VERSION 5.7 ;
  NOWIREEXTENSIONATPIN ON ;
  DIVIDERCHAR "/" ;
  BUSBITCHARS "[]" ;
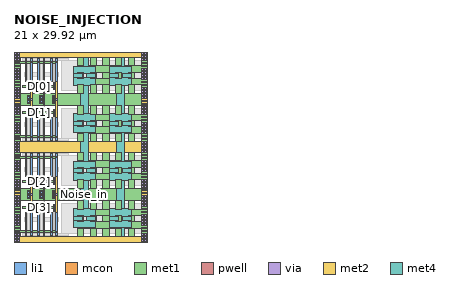
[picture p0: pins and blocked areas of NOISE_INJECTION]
MACRO NOISE_INJECTION
  CLASS BLOCK ;
  FOREIGN NOISE_INJECTION ;
  ORIGIN 0.000 0.000 ;
  SIZE 21.000 BY 29.920 ;
  PIN D[3]
    ANTENNAGATEAREA 0.378000 ;
    PORT
      LAYER li1 ;
        RECT 2.165 4.875 2.415 5.885 ;
        RECT 4.165 4.875 4.415 5.885 ;
        RECT 6.165 4.875 6.415 5.885 ;
      LAYER mcon ;
        RECT 2.205 5.295 2.375 5.465 ;
        RECT 4.205 5.295 4.375 5.465 ;
        RECT 6.205 5.295 6.375 5.465 ;
      LAYER met1 ;
        RECT 1.260 5.240 6.460 5.520 ;
    END
  END D[3]
  PIN VSS
    ANTENNADIFFAREA 3.813600 ;
    PORT
      LAYER pwell ;
        RECT 2.075 21.750 2.505 23.130 ;
        RECT 4.075 21.750 4.505 23.130 ;
        RECT 6.075 21.750 6.505 23.130 ;
        RECT 2.075 6.790 2.505 8.170 ;
        RECT 4.075 6.790 4.505 8.170 ;
        RECT 6.075 6.790 6.505 8.170 ;
      LAYER li1 ;
        RECT 1.735 25.295 1.985 28.825 ;
        RECT 2.595 25.295 2.845 28.825 ;
        RECT 3.735 25.295 3.985 28.825 ;
        RECT 4.595 25.295 4.845 28.825 ;
        RECT 5.735 25.295 5.985 28.825 ;
        RECT 6.595 25.295 6.845 28.825 ;
        RECT 2.165 21.935 2.415 22.945 ;
        RECT 4.165 21.935 4.415 22.945 ;
        RECT 6.165 21.935 6.415 22.945 ;
        RECT 1.735 16.055 1.985 19.585 ;
        RECT 2.595 16.055 2.845 19.585 ;
        RECT 3.735 16.055 3.985 19.585 ;
        RECT 4.595 16.055 4.845 19.585 ;
        RECT 5.735 16.055 5.985 19.585 ;
        RECT 6.595 16.055 6.845 19.585 ;
        RECT 1.735 10.335 1.985 13.865 ;
        RECT 2.595 10.335 2.845 13.865 ;
        RECT 3.735 10.335 3.985 13.865 ;
        RECT 4.595 10.335 4.845 13.865 ;
        RECT 5.735 10.335 5.985 13.865 ;
        RECT 6.595 10.335 6.845 13.865 ;
        RECT 2.165 6.975 2.415 7.985 ;
        RECT 4.165 6.975 4.415 7.985 ;
        RECT 6.165 6.975 6.415 7.985 ;
        RECT 1.735 1.095 1.985 4.625 ;
        RECT 2.595 1.095 2.845 4.625 ;
        RECT 3.735 1.095 3.985 4.625 ;
        RECT 4.595 1.095 4.845 4.625 ;
        RECT 5.735 1.095 5.985 4.625 ;
        RECT 6.595 1.095 6.845 4.625 ;
      LAYER mcon ;
        RECT 1.775 28.235 1.945 28.405 ;
        RECT 2.635 28.235 2.805 28.405 ;
        RECT 3.775 28.235 3.945 28.405 ;
        RECT 4.635 28.235 4.805 28.405 ;
        RECT 5.775 28.235 5.945 28.405 ;
        RECT 6.635 28.235 6.805 28.405 ;
        RECT 2.205 22.355 2.375 22.525 ;
        RECT 4.205 22.355 4.375 22.525 ;
        RECT 6.205 22.355 6.375 22.525 ;
        RECT 1.775 16.475 1.945 16.645 ;
        RECT 2.635 16.475 2.805 16.645 ;
        RECT 3.775 16.475 3.945 16.645 ;
        RECT 4.635 16.475 4.805 16.645 ;
        RECT 5.775 16.475 5.945 16.645 ;
        RECT 6.635 16.475 6.805 16.645 ;
        RECT 1.775 13.275 1.945 13.445 ;
        RECT 2.635 13.275 2.805 13.445 ;
        RECT 3.775 13.275 3.945 13.445 ;
        RECT 4.635 13.275 4.805 13.445 ;
        RECT 5.775 13.275 5.945 13.445 ;
        RECT 6.635 13.275 6.805 13.445 ;
        RECT 2.205 7.395 2.375 7.565 ;
        RECT 4.205 7.395 4.375 7.565 ;
        RECT 6.205 7.395 6.375 7.565 ;
        RECT 1.775 1.515 1.945 1.685 ;
        RECT 2.635 1.515 2.805 1.685 ;
        RECT 3.775 1.515 3.945 1.685 ;
        RECT 4.635 1.515 4.805 1.685 ;
        RECT 5.775 1.515 5.945 1.685 ;
        RECT 6.635 1.515 6.805 1.685 ;
      LAYER met1 ;
        RECT 0.000 29.060 21.000 29.920 ;
        RECT 0.000 28.460 1.000 29.060 ;
        RECT 0.000 28.180 6.890 28.460 ;
        RECT 0.000 23.460 1.000 28.180 ;
        RECT 10.000 27.770 11.000 29.060 ;
        RECT 12.000 27.770 13.000 29.060 ;
        RECT 14.000 27.770 15.000 29.060 ;
        RECT 16.000 27.770 17.000 29.060 ;
        RECT 18.000 27.770 19.000 29.060 ;
        RECT 20.000 27.770 21.000 29.060 ;
        RECT 10.000 26.770 21.000 27.770 ;
        RECT 10.000 25.760 11.000 26.770 ;
        RECT 12.000 25.760 13.000 26.770 ;
        RECT 14.000 25.760 15.000 26.770 ;
        RECT 16.000 25.760 17.000 26.770 ;
        RECT 18.000 25.760 19.000 26.770 ;
        RECT 20.000 25.760 21.000 26.770 ;
        RECT 10.000 24.760 21.000 25.760 ;
        RECT 10.000 23.460 11.000 24.760 ;
        RECT 12.000 23.460 13.000 24.760 ;
        RECT 14.000 23.460 15.000 24.760 ;
        RECT 16.000 23.460 17.000 24.760 ;
        RECT 18.000 23.460 19.000 24.760 ;
        RECT 20.000 23.460 21.000 24.760 ;
        RECT 0.000 21.420 21.000 23.460 ;
        RECT 0.000 16.700 1.000 21.420 ;
        RECT 10.000 20.120 11.000 21.420 ;
        RECT 12.000 20.120 13.000 21.420 ;
        RECT 14.000 20.120 15.000 21.420 ;
        RECT 16.000 20.120 17.000 21.420 ;
        RECT 18.000 20.120 19.000 21.420 ;
        RECT 20.000 20.120 21.000 21.420 ;
        RECT 10.000 19.120 21.000 20.120 ;
        RECT 10.000 18.120 11.000 19.120 ;
        RECT 12.000 18.120 13.000 19.120 ;
        RECT 14.000 18.120 15.000 19.120 ;
        RECT 16.000 18.120 17.000 19.120 ;
        RECT 18.000 18.120 19.000 19.120 ;
        RECT 20.000 18.120 21.000 19.120 ;
        RECT 10.000 17.120 21.000 18.120 ;
        RECT 0.000 16.420 6.890 16.700 ;
        RECT 0.000 15.820 1.000 16.420 ;
        RECT 10.000 15.820 11.000 17.120 ;
        RECT 12.000 15.820 13.000 17.120 ;
        RECT 14.000 15.820 15.000 17.120 ;
        RECT 16.000 15.820 17.000 17.120 ;
        RECT 18.000 15.820 19.000 17.120 ;
        RECT 20.000 15.820 21.000 17.120 ;
        RECT 0.000 14.100 21.000 15.820 ;
        RECT 0.000 13.500 1.000 14.100 ;
        RECT 0.000 13.220 6.890 13.500 ;
        RECT 0.000 8.500 1.000 13.220 ;
        RECT 10.000 12.810 11.000 14.100 ;
        RECT 12.000 12.810 13.000 14.100 ;
        RECT 14.000 12.810 15.000 14.100 ;
        RECT 16.000 12.810 17.000 14.100 ;
        RECT 18.000 12.810 19.000 14.100 ;
        RECT 20.000 12.810 21.000 14.100 ;
        RECT 10.000 11.810 21.000 12.810 ;
        RECT 10.000 10.800 11.000 11.810 ;
        RECT 12.000 10.800 13.000 11.810 ;
        RECT 14.000 10.800 15.000 11.810 ;
        RECT 16.000 10.800 17.000 11.810 ;
        RECT 18.000 10.800 19.000 11.810 ;
        RECT 20.000 10.800 21.000 11.810 ;
        RECT 10.000 9.800 21.000 10.800 ;
        RECT 10.000 8.500 11.000 9.800 ;
        RECT 12.000 8.500 13.000 9.800 ;
        RECT 14.000 8.500 15.000 9.800 ;
        RECT 16.000 8.500 17.000 9.800 ;
        RECT 18.000 8.500 19.000 9.800 ;
        RECT 20.000 8.500 21.000 9.800 ;
        RECT 0.000 6.460 21.000 8.500 ;
        RECT 0.000 1.740 1.000 6.460 ;
        RECT 10.000 5.160 11.000 6.460 ;
        RECT 12.000 5.160 13.000 6.460 ;
        RECT 14.000 5.160 15.000 6.460 ;
        RECT 16.000 5.160 17.000 6.460 ;
        RECT 18.000 5.160 19.000 6.460 ;
        RECT 20.000 5.160 21.000 6.460 ;
        RECT 10.000 4.160 21.000 5.160 ;
        RECT 10.000 3.160 11.000 4.160 ;
        RECT 12.000 3.160 13.000 4.160 ;
        RECT 14.000 3.160 15.000 4.160 ;
        RECT 16.000 3.160 17.000 4.160 ;
        RECT 18.000 3.160 19.000 4.160 ;
        RECT 20.000 3.160 21.000 4.160 ;
        RECT 10.000 2.160 21.000 3.160 ;
        RECT 0.000 1.460 6.890 1.740 ;
        RECT 0.000 0.860 1.000 1.460 ;
        RECT 10.000 0.860 11.000 2.160 ;
        RECT 12.000 0.860 13.000 2.160 ;
        RECT 14.000 0.860 15.000 2.160 ;
        RECT 16.000 0.860 17.000 2.160 ;
        RECT 18.000 0.860 19.000 2.160 ;
        RECT 20.000 0.860 21.000 2.160 ;
        RECT 0.000 0.000 21.000 0.860 ;
      LAYER via ;
        RECT 0.120 29.580 0.380 29.840 ;
        RECT 0.620 29.580 0.880 29.840 ;
        RECT 20.120 29.580 20.380 29.840 ;
        RECT 20.620 29.580 20.880 29.840 ;
        RECT 0.120 29.080 0.380 29.340 ;
        RECT 0.620 29.080 0.880 29.340 ;
        RECT 20.120 29.080 20.380 29.340 ;
        RECT 20.620 29.080 20.880 29.340 ;
        RECT 0.120 28.580 0.380 28.840 ;
        RECT 0.620 28.580 0.880 28.840 ;
        RECT 0.120 28.080 0.380 28.340 ;
        RECT 0.620 28.080 0.880 28.340 ;
        RECT 2.590 28.190 2.850 28.450 ;
        RECT 4.590 28.190 4.850 28.450 ;
        RECT 6.590 28.190 6.850 28.450 ;
        RECT 0.120 27.580 0.380 27.840 ;
        RECT 0.620 27.580 0.880 27.840 ;
        RECT 0.120 27.080 0.380 27.340 ;
        RECT 0.620 27.080 0.880 27.340 ;
        RECT 0.120 26.580 0.380 26.840 ;
        RECT 0.620 26.580 0.880 26.840 ;
        RECT 0.120 26.080 0.380 26.340 ;
        RECT 0.620 26.080 0.880 26.340 ;
        RECT 0.120 25.580 0.380 25.840 ;
        RECT 0.620 25.580 0.880 25.840 ;
        RECT 0.120 25.080 0.380 25.340 ;
        RECT 0.620 25.080 0.880 25.340 ;
        RECT 0.120 24.580 0.380 24.840 ;
        RECT 0.620 24.580 0.880 24.840 ;
        RECT 0.120 24.080 0.380 24.340 ;
        RECT 0.620 24.080 0.880 24.340 ;
        RECT 0.120 23.580 0.380 23.840 ;
        RECT 0.620 23.580 0.880 23.840 ;
        RECT 20.120 28.580 20.380 28.840 ;
        RECT 20.620 28.580 20.880 28.840 ;
        RECT 20.120 28.080 20.380 28.340 ;
        RECT 20.620 28.080 20.880 28.340 ;
        RECT 20.120 27.580 20.380 27.840 ;
        RECT 20.620 27.580 20.880 27.840 ;
        RECT 20.120 27.080 20.380 27.340 ;
        RECT 20.620 27.080 20.880 27.340 ;
        RECT 20.120 26.580 20.380 26.840 ;
        RECT 20.620 26.580 20.880 26.840 ;
        RECT 20.120 26.080 20.380 26.340 ;
        RECT 20.620 26.080 20.880 26.340 ;
        RECT 20.120 25.580 20.380 25.840 ;
        RECT 20.620 25.580 20.880 25.840 ;
        RECT 20.120 25.080 20.380 25.340 ;
        RECT 20.620 25.080 20.880 25.340 ;
        RECT 20.120 24.580 20.380 24.840 ;
        RECT 20.620 24.580 20.880 24.840 ;
        RECT 20.120 24.080 20.380 24.340 ;
        RECT 20.620 24.080 20.880 24.340 ;
        RECT 20.120 23.580 20.380 23.840 ;
        RECT 20.620 23.580 20.880 23.840 ;
        RECT 0.120 23.080 0.380 23.340 ;
        RECT 0.620 23.080 0.880 23.340 ;
        RECT 20.120 23.080 20.380 23.340 ;
        RECT 20.620 23.080 20.880 23.340 ;
        RECT 0.120 22.580 0.380 22.840 ;
        RECT 0.620 22.580 0.880 22.840 ;
        RECT 20.120 22.580 20.380 22.840 ;
        RECT 20.620 22.580 20.880 22.840 ;
        RECT 0.120 22.080 0.380 22.340 ;
        RECT 0.620 22.080 0.880 22.340 ;
        RECT 2.590 22.310 2.850 22.570 ;
        RECT 4.590 22.310 4.850 22.570 ;
        RECT 6.590 22.310 6.850 22.570 ;
        RECT 20.120 22.080 20.380 22.340 ;
        RECT 20.620 22.080 20.880 22.340 ;
        RECT 0.120 21.580 0.380 21.840 ;
        RECT 0.620 21.580 0.880 21.840 ;
        RECT 20.120 21.580 20.380 21.840 ;
        RECT 20.620 21.580 20.880 21.840 ;
        RECT 0.120 21.080 0.380 21.340 ;
        RECT 0.620 21.080 0.880 21.340 ;
        RECT 0.120 20.580 0.380 20.840 ;
        RECT 0.620 20.580 0.880 20.840 ;
        RECT 0.120 20.080 0.380 20.340 ;
        RECT 0.620 20.080 0.880 20.340 ;
        RECT 0.120 19.580 0.380 19.840 ;
        RECT 0.620 19.580 0.880 19.840 ;
        RECT 0.120 19.080 0.380 19.340 ;
        RECT 0.620 19.080 0.880 19.340 ;
        RECT 0.120 18.580 0.380 18.840 ;
        RECT 0.620 18.580 0.880 18.840 ;
        RECT 0.120 18.080 0.380 18.340 ;
        RECT 0.620 18.080 0.880 18.340 ;
        RECT 0.120 17.580 0.380 17.840 ;
        RECT 0.620 17.580 0.880 17.840 ;
        RECT 0.120 17.080 0.380 17.340 ;
        RECT 0.620 17.080 0.880 17.340 ;
        RECT 0.120 16.580 0.380 16.840 ;
        RECT 0.620 16.580 0.880 16.840 ;
        RECT 20.120 21.080 20.380 21.340 ;
        RECT 20.620 21.080 20.880 21.340 ;
        RECT 20.120 20.580 20.380 20.840 ;
        RECT 20.620 20.580 20.880 20.840 ;
        RECT 20.120 20.080 20.380 20.340 ;
        RECT 20.620 20.080 20.880 20.340 ;
        RECT 20.120 19.580 20.380 19.840 ;
        RECT 20.620 19.580 20.880 19.840 ;
        RECT 20.120 19.080 20.380 19.340 ;
        RECT 20.620 19.080 20.880 19.340 ;
        RECT 20.120 18.580 20.380 18.840 ;
        RECT 20.620 18.580 20.880 18.840 ;
        RECT 20.120 18.080 20.380 18.340 ;
        RECT 20.620 18.080 20.880 18.340 ;
        RECT 20.120 17.580 20.380 17.840 ;
        RECT 20.620 17.580 20.880 17.840 ;
        RECT 2.590 16.430 2.850 16.690 ;
        RECT 4.590 16.430 4.850 16.690 ;
        RECT 6.590 16.430 6.850 16.690 ;
        RECT 0.120 16.080 0.380 16.340 ;
        RECT 0.620 16.080 0.880 16.340 ;
        RECT 0.120 15.580 0.380 15.840 ;
        RECT 0.620 15.580 0.880 15.840 ;
        RECT 20.120 17.080 20.380 17.340 ;
        RECT 20.620 17.080 20.880 17.340 ;
        RECT 20.120 16.580 20.380 16.840 ;
        RECT 20.620 16.580 20.880 16.840 ;
        RECT 20.120 16.080 20.380 16.340 ;
        RECT 20.620 16.080 20.880 16.340 ;
        RECT 20.120 15.580 20.380 15.840 ;
        RECT 20.620 15.580 20.880 15.840 ;
        RECT 0.120 15.080 0.380 15.340 ;
        RECT 0.620 15.080 0.880 15.340 ;
        RECT 20.120 15.080 20.380 15.340 ;
        RECT 20.620 15.080 20.880 15.340 ;
        RECT 0.120 14.580 0.380 14.840 ;
        RECT 0.620 14.580 0.880 14.840 ;
        RECT 20.120 14.580 20.380 14.840 ;
        RECT 20.620 14.580 20.880 14.840 ;
        RECT 0.120 14.080 0.380 14.340 ;
        RECT 0.620 14.080 0.880 14.340 ;
        RECT 0.120 13.580 0.380 13.840 ;
        RECT 0.620 13.580 0.880 13.840 ;
        RECT 0.120 13.080 0.380 13.340 ;
        RECT 0.620 13.080 0.880 13.340 ;
        RECT 2.590 13.230 2.850 13.490 ;
        RECT 4.590 13.230 4.850 13.490 ;
        RECT 6.590 13.230 6.850 13.490 ;
        RECT 0.120 12.580 0.380 12.840 ;
        RECT 0.620 12.580 0.880 12.840 ;
        RECT 0.120 12.080 0.380 12.340 ;
        RECT 0.620 12.080 0.880 12.340 ;
        RECT 0.120 11.580 0.380 11.840 ;
        RECT 0.620 11.580 0.880 11.840 ;
        RECT 0.120 11.080 0.380 11.340 ;
        RECT 0.620 11.080 0.880 11.340 ;
        RECT 0.120 10.580 0.380 10.840 ;
        RECT 0.620 10.580 0.880 10.840 ;
        RECT 0.120 10.080 0.380 10.340 ;
        RECT 0.620 10.080 0.880 10.340 ;
        RECT 0.120 9.580 0.380 9.840 ;
        RECT 0.620 9.580 0.880 9.840 ;
        RECT 0.120 9.080 0.380 9.340 ;
        RECT 0.620 9.080 0.880 9.340 ;
        RECT 0.120 8.580 0.380 8.840 ;
        RECT 0.620 8.580 0.880 8.840 ;
        RECT 20.120 14.080 20.380 14.340 ;
        RECT 20.620 14.080 20.880 14.340 ;
        RECT 20.120 13.580 20.380 13.840 ;
        RECT 20.620 13.580 20.880 13.840 ;
        RECT 20.120 13.080 20.380 13.340 ;
        RECT 20.620 13.080 20.880 13.340 ;
        RECT 20.120 12.580 20.380 12.840 ;
        RECT 20.620 12.580 20.880 12.840 ;
        RECT 20.120 12.080 20.380 12.340 ;
        RECT 20.620 12.080 20.880 12.340 ;
        RECT 20.120 11.580 20.380 11.840 ;
        RECT 20.620 11.580 20.880 11.840 ;
        RECT 20.120 11.080 20.380 11.340 ;
        RECT 20.620 11.080 20.880 11.340 ;
        RECT 20.120 10.580 20.380 10.840 ;
        RECT 20.620 10.580 20.880 10.840 ;
        RECT 20.120 10.080 20.380 10.340 ;
        RECT 20.620 10.080 20.880 10.340 ;
        RECT 20.120 9.580 20.380 9.840 ;
        RECT 20.620 9.580 20.880 9.840 ;
        RECT 20.120 9.080 20.380 9.340 ;
        RECT 20.620 9.080 20.880 9.340 ;
        RECT 20.120 8.580 20.380 8.840 ;
        RECT 20.620 8.580 20.880 8.840 ;
        RECT 0.120 8.080 0.380 8.340 ;
        RECT 0.620 8.080 0.880 8.340 ;
        RECT 20.120 8.080 20.380 8.340 ;
        RECT 20.620 8.080 20.880 8.340 ;
        RECT 0.120 7.580 0.380 7.840 ;
        RECT 0.620 7.580 0.880 7.840 ;
        RECT 2.590 7.350 2.850 7.610 ;
        RECT 4.590 7.350 4.850 7.610 ;
        RECT 6.590 7.350 6.850 7.610 ;
        RECT 20.120 7.580 20.380 7.840 ;
        RECT 20.620 7.580 20.880 7.840 ;
        RECT 0.120 7.080 0.380 7.340 ;
        RECT 0.620 7.080 0.880 7.340 ;
        RECT 20.120 7.080 20.380 7.340 ;
        RECT 20.620 7.080 20.880 7.340 ;
        RECT 0.120 6.580 0.380 6.840 ;
        RECT 0.620 6.580 0.880 6.840 ;
        RECT 20.120 6.580 20.380 6.840 ;
        RECT 20.620 6.580 20.880 6.840 ;
        RECT 0.120 6.080 0.380 6.340 ;
        RECT 0.620 6.080 0.880 6.340 ;
        RECT 0.120 5.580 0.380 5.840 ;
        RECT 0.620 5.580 0.880 5.840 ;
        RECT 0.120 5.080 0.380 5.340 ;
        RECT 0.620 5.080 0.880 5.340 ;
        RECT 0.120 4.580 0.380 4.840 ;
        RECT 0.620 4.580 0.880 4.840 ;
        RECT 0.120 4.080 0.380 4.340 ;
        RECT 0.620 4.080 0.880 4.340 ;
        RECT 0.120 3.580 0.380 3.840 ;
        RECT 0.620 3.580 0.880 3.840 ;
        RECT 0.120 3.080 0.380 3.340 ;
        RECT 0.620 3.080 0.880 3.340 ;
        RECT 0.120 2.580 0.380 2.840 ;
        RECT 0.620 2.580 0.880 2.840 ;
        RECT 0.120 2.080 0.380 2.340 ;
        RECT 0.620 2.080 0.880 2.340 ;
        RECT 0.120 1.580 0.380 1.840 ;
        RECT 0.620 1.580 0.880 1.840 ;
        RECT 20.120 6.080 20.380 6.340 ;
        RECT 20.620 6.080 20.880 6.340 ;
        RECT 20.120 5.580 20.380 5.840 ;
        RECT 20.620 5.580 20.880 5.840 ;
        RECT 20.120 5.080 20.380 5.340 ;
        RECT 20.620 5.080 20.880 5.340 ;
        RECT 20.120 4.580 20.380 4.840 ;
        RECT 20.620 4.580 20.880 4.840 ;
        RECT 20.120 4.080 20.380 4.340 ;
        RECT 20.620 4.080 20.880 4.340 ;
        RECT 20.120 3.580 20.380 3.840 ;
        RECT 20.620 3.580 20.880 3.840 ;
        RECT 20.120 3.080 20.380 3.340 ;
        RECT 20.620 3.080 20.880 3.340 ;
        RECT 20.120 2.580 20.380 2.840 ;
        RECT 20.620 2.580 20.880 2.840 ;
        RECT 2.590 1.470 2.850 1.730 ;
        RECT 4.590 1.470 4.850 1.730 ;
        RECT 6.590 1.470 6.850 1.730 ;
        RECT 0.120 1.080 0.380 1.340 ;
        RECT 0.620 1.080 0.880 1.340 ;
        RECT 20.120 2.080 20.380 2.340 ;
        RECT 20.620 2.080 20.880 2.340 ;
        RECT 20.120 1.580 20.380 1.840 ;
        RECT 20.620 1.580 20.880 1.840 ;
        RECT 20.120 1.080 20.380 1.340 ;
        RECT 20.620 1.080 20.880 1.340 ;
        RECT 0.120 0.580 0.380 0.840 ;
        RECT 0.620 0.580 0.880 0.840 ;
        RECT 20.120 0.580 20.380 0.840 ;
        RECT 20.620 0.580 20.880 0.840 ;
        RECT 0.120 0.080 0.380 0.340 ;
        RECT 0.620 0.080 0.880 0.340 ;
        RECT 20.120 0.080 20.380 0.340 ;
        RECT 20.620 0.080 20.880 0.340 ;
      LAYER met2 ;
        RECT 0.000 29.060 21.000 29.920 ;
        RECT 0.000 15.820 1.000 29.060 ;
        RECT 2.580 16.400 2.860 28.480 ;
        RECT 4.580 16.400 4.860 28.480 ;
        RECT 6.580 16.400 6.860 28.480 ;
        RECT 20.000 15.820 21.000 29.060 ;
        RECT 0.000 14.100 21.000 15.820 ;
        RECT 0.000 0.860 1.000 14.100 ;
        RECT 2.580 1.440 2.860 13.520 ;
        RECT 4.580 1.440 4.860 13.520 ;
        RECT 6.580 1.440 6.860 13.520 ;
        RECT 20.000 0.860 21.000 14.100 ;
        RECT 0.000 0.000 21.000 0.860 ;
    END
  END VSS
  PIN D[2]
    ANTENNAGATEAREA 0.378000 ;
    PORT
      LAYER li1 ;
        RECT 2.165 9.075 2.415 10.085 ;
        RECT 4.165 9.075 4.415 10.085 ;
        RECT 6.165 9.075 6.415 10.085 ;
      LAYER mcon ;
        RECT 2.205 9.495 2.375 9.665 ;
        RECT 4.205 9.495 4.375 9.665 ;
        RECT 6.205 9.495 6.375 9.665 ;
      LAYER met1 ;
        RECT 1.260 9.440 6.460 9.720 ;
    END
  END D[2]
  PIN D[1]
    ANTENNAGATEAREA 0.378000 ;
    PORT
      LAYER li1 ;
        RECT 2.165 19.835 2.415 20.845 ;
        RECT 4.165 19.835 4.415 20.845 ;
        RECT 6.165 19.835 6.415 20.845 ;
      LAYER mcon ;
        RECT 2.205 20.255 2.375 20.425 ;
        RECT 4.205 20.255 4.375 20.425 ;
        RECT 6.205 20.255 6.375 20.425 ;
      LAYER met1 ;
        RECT 1.260 20.200 6.460 20.480 ;
    END
  END D[1]
  PIN D[0]
    ANTENNAGATEAREA 0.378000 ;
    PORT
      LAYER li1 ;
        RECT 2.165 24.035 2.415 25.045 ;
        RECT 4.165 24.035 4.415 25.045 ;
        RECT 6.165 24.035 6.415 25.045 ;
      LAYER mcon ;
        RECT 2.205 24.455 2.375 24.625 ;
        RECT 4.205 24.455 4.375 24.625 ;
        RECT 6.205 24.455 6.375 24.625 ;
      LAYER met1 ;
        RECT 1.260 24.400 6.460 24.680 ;
    END
  END D[0]
  PIN Noise_in
    PORT
      LAYER met4 ;
        RECT 10.500 27.710 11.700 29.060 ;
        RECT 9.300 26.510 12.900 27.710 ;
        RECT 9.300 25.910 10.800 26.510 ;
        RECT 11.400 25.910 12.900 26.510 ;
        RECT 9.300 24.710 12.900 25.910 ;
        RECT 10.500 20.170 11.700 24.710 ;
        RECT 9.300 18.970 12.900 20.170 ;
        RECT 9.300 18.370 10.800 18.970 ;
        RECT 11.400 18.370 12.900 18.970 ;
        RECT 9.300 17.170 12.900 18.370 ;
        RECT 10.500 12.750 11.700 17.170 ;
        RECT 9.300 11.550 12.900 12.750 ;
        RECT 9.300 10.950 10.800 11.550 ;
        RECT 11.400 10.950 12.900 11.550 ;
        RECT 9.300 9.750 12.900 10.950 ;
        RECT 10.500 5.210 11.700 9.750 ;
        RECT 9.300 4.010 12.900 5.210 ;
        RECT 9.300 3.410 10.800 4.010 ;
        RECT 11.400 3.410 12.900 4.010 ;
        RECT 9.300 2.210 12.900 3.410 ;
    END
  END Noise_in
  PIN bias_out
    PORT
      LAYER met4 ;
        RECT 16.170 27.710 17.370 29.060 ;
        RECT 14.970 26.510 18.570 27.710 ;
        RECT 14.970 25.910 16.470 26.510 ;
        RECT 17.070 25.910 18.570 26.510 ;
        RECT 14.970 24.710 18.570 25.910 ;
        RECT 16.170 20.170 17.370 24.710 ;
        RECT 14.970 18.970 18.570 20.170 ;
        RECT 14.970 18.370 16.470 18.970 ;
        RECT 17.070 18.370 18.570 18.970 ;
        RECT 14.970 17.170 18.570 18.370 ;
        RECT 16.170 12.750 17.370 17.170 ;
        RECT 14.970 11.550 18.570 12.750 ;
        RECT 14.970 10.950 16.470 11.550 ;
        RECT 17.070 10.950 18.570 11.550 ;
        RECT 14.970 9.750 18.570 10.950 ;
        RECT 16.170 5.210 17.370 9.750 ;
        RECT 14.970 4.010 18.570 5.210 ;
        RECT 14.970 3.410 16.470 4.010 ;
        RECT 17.070 3.410 18.570 4.010 ;
        RECT 14.970 2.210 18.570 3.410 ;
        RECT 16.170 0.860 17.370 2.210 ;
    END
  END bias_out
  OBS
      LAYER pwell ;
        RECT 1.605 25.985 6.975 26.665 ;
        RECT 1.605 18.215 6.975 18.895 ;
        RECT 1.605 11.025 6.975 11.705 ;
        RECT 1.605 3.255 6.975 3.935 ;
      LAYER li1 ;
        RECT 2.165 25.295 2.415 28.825 ;
        RECT 4.165 25.295 4.415 28.825 ;
        RECT 6.165 25.295 6.415 28.825 ;
        RECT 2.165 16.055 2.415 19.585 ;
        RECT 4.165 16.055 4.415 19.585 ;
        RECT 6.165 16.055 6.415 19.585 ;
        RECT 2.165 10.335 2.415 13.865 ;
        RECT 4.165 10.335 4.415 13.865 ;
        RECT 6.165 10.335 6.415 13.865 ;
        RECT 2.165 1.095 2.415 4.625 ;
        RECT 4.165 1.095 4.415 4.625 ;
        RECT 6.165 1.095 6.415 4.625 ;
      LAYER mcon ;
        RECT 2.205 28.655 2.375 28.825 ;
        RECT 4.205 28.655 4.375 28.825 ;
        RECT 6.205 28.655 6.375 28.825 ;
        RECT 2.205 16.055 2.375 16.225 ;
        RECT 4.205 16.055 4.375 16.225 ;
        RECT 6.205 16.055 6.375 16.225 ;
        RECT 2.205 13.695 2.375 13.865 ;
        RECT 4.205 13.695 4.375 13.865 ;
        RECT 6.205 13.695 6.375 13.865 ;
        RECT 2.205 1.095 2.375 1.265 ;
        RECT 4.205 1.095 4.375 1.265 ;
        RECT 6.205 1.095 6.375 1.265 ;
      LAYER met1 ;
        RECT 1.260 28.600 8.650 28.880 ;
        RECT 7.650 24.010 8.650 28.600 ;
        RECT 7.650 16.280 8.650 20.870 ;
        RECT 1.260 16.000 8.650 16.280 ;
        RECT 1.260 13.640 8.650 13.920 ;
        RECT 7.650 9.050 8.650 13.640 ;
        RECT 7.650 1.320 8.650 5.910 ;
        RECT 1.260 1.040 8.650 1.320 ;
      LAYER via ;
        RECT 7.770 28.080 8.030 28.340 ;
        RECT 8.270 28.080 8.530 28.340 ;
        RECT 7.770 27.580 8.030 27.840 ;
        RECT 8.270 27.580 8.530 27.840 ;
        RECT 7.770 27.080 8.030 27.340 ;
        RECT 8.270 27.080 8.530 27.340 ;
        RECT 7.770 26.580 8.030 26.840 ;
        RECT 8.270 26.580 8.530 26.840 ;
        RECT 7.770 26.080 8.030 26.340 ;
        RECT 8.270 26.080 8.530 26.340 ;
        RECT 7.770 25.580 8.030 25.840 ;
        RECT 8.270 25.580 8.530 25.840 ;
        RECT 7.770 25.080 8.030 25.340 ;
        RECT 8.270 25.080 8.530 25.340 ;
        RECT 7.770 24.580 8.030 24.840 ;
        RECT 8.270 24.580 8.530 24.840 ;
        RECT 7.770 24.080 8.030 24.340 ;
        RECT 8.270 24.080 8.530 24.340 ;
        RECT 7.770 20.540 8.030 20.800 ;
        RECT 8.270 20.540 8.530 20.800 ;
        RECT 7.770 20.040 8.030 20.300 ;
        RECT 8.270 20.040 8.530 20.300 ;
        RECT 7.770 19.540 8.030 19.800 ;
        RECT 8.270 19.540 8.530 19.800 ;
        RECT 7.770 19.040 8.030 19.300 ;
        RECT 8.270 19.040 8.530 19.300 ;
        RECT 7.770 18.540 8.030 18.800 ;
        RECT 8.270 18.540 8.530 18.800 ;
        RECT 7.770 18.040 8.030 18.300 ;
        RECT 8.270 18.040 8.530 18.300 ;
        RECT 7.770 17.540 8.030 17.800 ;
        RECT 8.270 17.540 8.530 17.800 ;
        RECT 7.770 17.040 8.030 17.300 ;
        RECT 8.270 17.040 8.530 17.300 ;
        RECT 7.770 16.540 8.030 16.800 ;
        RECT 8.270 16.540 8.530 16.800 ;
        RECT 7.770 13.120 8.030 13.380 ;
        RECT 8.270 13.120 8.530 13.380 ;
        RECT 7.770 12.620 8.030 12.880 ;
        RECT 8.270 12.620 8.530 12.880 ;
        RECT 7.770 12.120 8.030 12.380 ;
        RECT 8.270 12.120 8.530 12.380 ;
        RECT 7.770 11.620 8.030 11.880 ;
        RECT 8.270 11.620 8.530 11.880 ;
        RECT 7.770 11.120 8.030 11.380 ;
        RECT 8.270 11.120 8.530 11.380 ;
        RECT 7.770 10.620 8.030 10.880 ;
        RECT 8.270 10.620 8.530 10.880 ;
        RECT 7.770 10.120 8.030 10.380 ;
        RECT 8.270 10.120 8.530 10.380 ;
        RECT 7.770 9.620 8.030 9.880 ;
        RECT 8.270 9.620 8.530 9.880 ;
        RECT 7.770 9.120 8.030 9.380 ;
        RECT 8.270 9.120 8.530 9.380 ;
        RECT 7.770 5.580 8.030 5.840 ;
        RECT 8.270 5.580 8.530 5.840 ;
        RECT 7.770 5.080 8.030 5.340 ;
        RECT 8.270 5.080 8.530 5.340 ;
        RECT 7.770 4.580 8.030 4.840 ;
        RECT 8.270 4.580 8.530 4.840 ;
        RECT 7.770 4.080 8.030 4.340 ;
        RECT 8.270 4.080 8.530 4.340 ;
        RECT 7.770 3.580 8.030 3.840 ;
        RECT 8.270 3.580 8.530 3.840 ;
        RECT 7.770 3.080 8.030 3.340 ;
        RECT 8.270 3.080 8.530 3.340 ;
        RECT 7.770 2.580 8.030 2.840 ;
        RECT 8.270 2.580 8.530 2.840 ;
        RECT 7.770 2.080 8.030 2.340 ;
        RECT 8.270 2.080 8.530 2.340 ;
        RECT 7.770 1.580 8.030 1.840 ;
        RECT 8.270 1.580 8.530 1.840 ;
      LAYER met2 ;
        RECT 7.650 24.010 8.650 28.410 ;
        RECT 7.650 16.470 8.650 20.870 ;
        RECT 7.650 9.050 8.650 13.450 ;
        RECT 7.650 1.510 8.650 5.910 ;
      LAYER via2 ;
        RECT 7.760 28.070 8.040 28.350 ;
        RECT 8.260 28.070 8.540 28.350 ;
        RECT 7.760 27.570 8.040 27.850 ;
        RECT 8.260 27.570 8.540 27.850 ;
        RECT 7.760 27.070 8.040 27.350 ;
        RECT 8.260 27.070 8.540 27.350 ;
        RECT 7.760 26.570 8.040 26.850 ;
        RECT 8.260 26.570 8.540 26.850 ;
        RECT 7.760 26.070 8.040 26.350 ;
        RECT 8.260 26.070 8.540 26.350 ;
        RECT 7.760 25.570 8.040 25.850 ;
        RECT 8.260 25.570 8.540 25.850 ;
        RECT 7.760 25.070 8.040 25.350 ;
        RECT 8.260 25.070 8.540 25.350 ;
        RECT 7.760 24.570 8.040 24.850 ;
        RECT 8.260 24.570 8.540 24.850 ;
        RECT 7.760 24.070 8.040 24.350 ;
        RECT 8.260 24.070 8.540 24.350 ;
        RECT 7.760 20.530 8.040 20.810 ;
        RECT 8.260 20.530 8.540 20.810 ;
        RECT 7.760 20.030 8.040 20.310 ;
        RECT 8.260 20.030 8.540 20.310 ;
        RECT 7.760 19.530 8.040 19.810 ;
        RECT 8.260 19.530 8.540 19.810 ;
        RECT 7.760 19.030 8.040 19.310 ;
        RECT 8.260 19.030 8.540 19.310 ;
        RECT 7.760 18.530 8.040 18.810 ;
        RECT 8.260 18.530 8.540 18.810 ;
        RECT 7.760 18.030 8.040 18.310 ;
        RECT 8.260 18.030 8.540 18.310 ;
        RECT 7.760 17.530 8.040 17.810 ;
        RECT 8.260 17.530 8.540 17.810 ;
        RECT 7.760 17.030 8.040 17.310 ;
        RECT 8.260 17.030 8.540 17.310 ;
        RECT 7.760 16.530 8.040 16.810 ;
        RECT 8.260 16.530 8.540 16.810 ;
        RECT 7.760 13.110 8.040 13.390 ;
        RECT 8.260 13.110 8.540 13.390 ;
        RECT 7.760 12.610 8.040 12.890 ;
        RECT 8.260 12.610 8.540 12.890 ;
        RECT 7.760 12.110 8.040 12.390 ;
        RECT 8.260 12.110 8.540 12.390 ;
        RECT 7.760 11.610 8.040 11.890 ;
        RECT 8.260 11.610 8.540 11.890 ;
        RECT 7.760 11.110 8.040 11.390 ;
        RECT 8.260 11.110 8.540 11.390 ;
        RECT 7.760 10.610 8.040 10.890 ;
        RECT 8.260 10.610 8.540 10.890 ;
        RECT 7.760 10.110 8.040 10.390 ;
        RECT 8.260 10.110 8.540 10.390 ;
        RECT 7.760 9.610 8.040 9.890 ;
        RECT 8.260 9.610 8.540 9.890 ;
        RECT 7.760 9.110 8.040 9.390 ;
        RECT 8.260 9.110 8.540 9.390 ;
        RECT 7.760 5.570 8.040 5.850 ;
        RECT 8.260 5.570 8.540 5.850 ;
        RECT 7.760 5.070 8.040 5.350 ;
        RECT 8.260 5.070 8.540 5.350 ;
        RECT 7.760 4.570 8.040 4.850 ;
        RECT 8.260 4.570 8.540 4.850 ;
        RECT 7.760 4.070 8.040 4.350 ;
        RECT 8.260 4.070 8.540 4.350 ;
        RECT 7.760 3.570 8.040 3.850 ;
        RECT 8.260 3.570 8.540 3.850 ;
        RECT 7.760 3.070 8.040 3.350 ;
        RECT 8.260 3.070 8.540 3.350 ;
        RECT 7.760 2.570 8.040 2.850 ;
        RECT 8.260 2.570 8.540 2.850 ;
        RECT 7.760 2.070 8.040 2.350 ;
        RECT 8.260 2.070 8.540 2.350 ;
        RECT 7.760 1.570 8.040 1.850 ;
        RECT 8.260 1.570 8.540 1.850 ;
      LAYER met3 ;
        RECT 7.650 24.010 20.220 28.410 ;
        RECT 7.650 16.470 20.220 20.870 ;
        RECT 7.650 9.050 20.220 13.450 ;
        RECT 7.650 1.510 20.220 5.910 ;
      LAYER via3 ;
        RECT 8.105 27.850 8.425 28.170 ;
        RECT 13.775 27.850 14.095 28.170 ;
        RECT 19.445 27.850 19.765 28.170 ;
        RECT 8.105 27.450 8.425 27.770 ;
        RECT 13.775 27.450 14.095 27.770 ;
        RECT 19.445 27.450 19.765 27.770 ;
        RECT 8.105 27.050 8.425 27.370 ;
        RECT 13.775 27.050 14.095 27.370 ;
        RECT 19.445 27.050 19.765 27.370 ;
        RECT 8.105 26.650 8.425 26.970 ;
        RECT 13.775 26.650 14.095 26.970 ;
        RECT 19.445 26.650 19.765 26.970 ;
        RECT 8.105 26.250 8.425 26.570 ;
        RECT 13.775 26.250 14.095 26.570 ;
        RECT 19.445 26.250 19.765 26.570 ;
        RECT 8.105 25.850 8.425 26.170 ;
        RECT 13.775 25.850 14.095 26.170 ;
        RECT 19.445 25.850 19.765 26.170 ;
        RECT 8.105 25.450 8.425 25.770 ;
        RECT 13.775 25.450 14.095 25.770 ;
        RECT 19.445 25.450 19.765 25.770 ;
        RECT 8.105 25.050 8.425 25.370 ;
        RECT 13.775 25.050 14.095 25.370 ;
        RECT 19.445 25.050 19.765 25.370 ;
        RECT 8.105 24.650 8.425 24.970 ;
        RECT 13.775 24.650 14.095 24.970 ;
        RECT 19.445 24.650 19.765 24.970 ;
        RECT 8.105 24.250 8.425 24.570 ;
        RECT 13.775 24.250 14.095 24.570 ;
        RECT 19.445 24.250 19.765 24.570 ;
        RECT 8.105 20.310 8.425 20.630 ;
        RECT 13.775 20.310 14.095 20.630 ;
        RECT 19.445 20.310 19.765 20.630 ;
        RECT 8.105 19.910 8.425 20.230 ;
        RECT 13.775 19.910 14.095 20.230 ;
        RECT 19.445 19.910 19.765 20.230 ;
        RECT 8.105 19.510 8.425 19.830 ;
        RECT 13.775 19.510 14.095 19.830 ;
        RECT 19.445 19.510 19.765 19.830 ;
        RECT 8.105 19.110 8.425 19.430 ;
        RECT 13.775 19.110 14.095 19.430 ;
        RECT 19.445 19.110 19.765 19.430 ;
        RECT 8.105 18.710 8.425 19.030 ;
        RECT 13.775 18.710 14.095 19.030 ;
        RECT 19.445 18.710 19.765 19.030 ;
        RECT 8.105 18.310 8.425 18.630 ;
        RECT 13.775 18.310 14.095 18.630 ;
        RECT 19.445 18.310 19.765 18.630 ;
        RECT 8.105 17.910 8.425 18.230 ;
        RECT 13.775 17.910 14.095 18.230 ;
        RECT 19.445 17.910 19.765 18.230 ;
        RECT 8.105 17.510 8.425 17.830 ;
        RECT 13.775 17.510 14.095 17.830 ;
        RECT 19.445 17.510 19.765 17.830 ;
        RECT 8.105 17.110 8.425 17.430 ;
        RECT 13.775 17.110 14.095 17.430 ;
        RECT 19.445 17.110 19.765 17.430 ;
        RECT 8.105 16.710 8.425 17.030 ;
        RECT 13.775 16.710 14.095 17.030 ;
        RECT 19.445 16.710 19.765 17.030 ;
        RECT 8.105 12.890 8.425 13.210 ;
        RECT 13.775 12.890 14.095 13.210 ;
        RECT 19.445 12.890 19.765 13.210 ;
        RECT 8.105 12.490 8.425 12.810 ;
        RECT 13.775 12.490 14.095 12.810 ;
        RECT 19.445 12.490 19.765 12.810 ;
        RECT 8.105 12.090 8.425 12.410 ;
        RECT 13.775 12.090 14.095 12.410 ;
        RECT 19.445 12.090 19.765 12.410 ;
        RECT 8.105 11.690 8.425 12.010 ;
        RECT 13.775 11.690 14.095 12.010 ;
        RECT 19.445 11.690 19.765 12.010 ;
        RECT 8.105 11.290 8.425 11.610 ;
        RECT 13.775 11.290 14.095 11.610 ;
        RECT 19.445 11.290 19.765 11.610 ;
        RECT 8.105 10.890 8.425 11.210 ;
        RECT 13.775 10.890 14.095 11.210 ;
        RECT 19.445 10.890 19.765 11.210 ;
        RECT 8.105 10.490 8.425 10.810 ;
        RECT 13.775 10.490 14.095 10.810 ;
        RECT 19.445 10.490 19.765 10.810 ;
        RECT 8.105 10.090 8.425 10.410 ;
        RECT 13.775 10.090 14.095 10.410 ;
        RECT 19.445 10.090 19.765 10.410 ;
        RECT 8.105 9.690 8.425 10.010 ;
        RECT 13.775 9.690 14.095 10.010 ;
        RECT 19.445 9.690 19.765 10.010 ;
        RECT 8.105 9.290 8.425 9.610 ;
        RECT 13.775 9.290 14.095 9.610 ;
        RECT 19.445 9.290 19.765 9.610 ;
        RECT 8.105 5.350 8.425 5.670 ;
        RECT 13.775 5.350 14.095 5.670 ;
        RECT 19.445 5.350 19.765 5.670 ;
        RECT 8.105 4.950 8.425 5.270 ;
        RECT 13.775 4.950 14.095 5.270 ;
        RECT 19.445 4.950 19.765 5.270 ;
        RECT 8.105 4.550 8.425 4.870 ;
        RECT 13.775 4.550 14.095 4.870 ;
        RECT 19.445 4.550 19.765 4.870 ;
        RECT 8.105 4.150 8.425 4.470 ;
        RECT 13.775 4.150 14.095 4.470 ;
        RECT 19.445 4.150 19.765 4.470 ;
        RECT 8.105 3.750 8.425 4.070 ;
        RECT 13.775 3.750 14.095 4.070 ;
        RECT 19.445 3.750 19.765 4.070 ;
        RECT 8.105 3.350 8.425 3.670 ;
        RECT 13.775 3.350 14.095 3.670 ;
        RECT 19.445 3.350 19.765 3.670 ;
        RECT 8.105 2.950 8.425 3.270 ;
        RECT 13.775 2.950 14.095 3.270 ;
        RECT 19.445 2.950 19.765 3.270 ;
        RECT 8.105 2.550 8.425 2.870 ;
        RECT 13.775 2.550 14.095 2.870 ;
        RECT 19.445 2.550 19.765 2.870 ;
        RECT 8.105 2.150 8.425 2.470 ;
        RECT 13.775 2.150 14.095 2.470 ;
        RECT 19.445 2.150 19.765 2.470 ;
        RECT 8.105 1.750 8.425 2.070 ;
        RECT 13.775 1.750 14.095 2.070 ;
        RECT 19.445 1.750 19.765 2.070 ;
      LAYER met4 ;
        RECT 7.650 24.010 8.880 28.410 ;
        RECT 13.320 24.010 14.550 28.410 ;
        RECT 18.990 24.010 20.220 28.410 ;
        RECT 7.650 16.470 8.880 20.870 ;
        RECT 13.320 16.470 14.550 20.870 ;
        RECT 18.990 16.470 20.220 20.870 ;
        RECT 7.650 9.050 8.880 13.450 ;
        RECT 13.320 9.050 14.550 13.450 ;
        RECT 18.990 9.050 20.220 13.450 ;
        RECT 7.650 1.510 8.880 5.910 ;
        RECT 13.320 1.510 14.550 5.910 ;
        RECT 18.990 1.510 20.220 5.910 ;
      LAYER via4 ;
        RECT 7.675 27.200 8.855 28.380 ;
        RECT 7.675 24.040 8.855 25.220 ;
        RECT 13.345 27.200 14.525 28.380 ;
        RECT 13.345 24.040 14.525 25.220 ;
        RECT 19.015 27.200 20.195 28.380 ;
        RECT 19.015 24.040 20.195 25.220 ;
        RECT 7.675 19.660 8.855 20.840 ;
        RECT 7.675 16.500 8.855 17.680 ;
        RECT 13.345 19.660 14.525 20.840 ;
        RECT 13.345 16.500 14.525 17.680 ;
        RECT 19.015 19.660 20.195 20.840 ;
        RECT 19.015 16.500 20.195 17.680 ;
        RECT 7.675 12.240 8.855 13.420 ;
        RECT 7.675 9.080 8.855 10.260 ;
        RECT 13.345 12.240 14.525 13.420 ;
        RECT 13.345 9.080 14.525 10.260 ;
        RECT 19.015 12.240 20.195 13.420 ;
        RECT 19.015 9.080 20.195 10.260 ;
        RECT 7.675 4.700 8.855 5.880 ;
        RECT 7.675 1.540 8.855 2.720 ;
        RECT 13.345 4.700 14.525 5.880 ;
        RECT 13.345 1.540 14.525 2.720 ;
        RECT 19.015 4.700 20.195 5.880 ;
        RECT 19.015 1.540 20.195 2.720 ;
      LAYER met5 ;
        RECT 7.550 23.910 20.320 28.510 ;
        RECT 7.550 16.370 20.320 20.970 ;
        RECT 7.550 8.950 20.320 13.550 ;
        RECT 7.550 1.410 20.320 6.010 ;
  END
END NOISE_INJECTION
END LIBRARY
